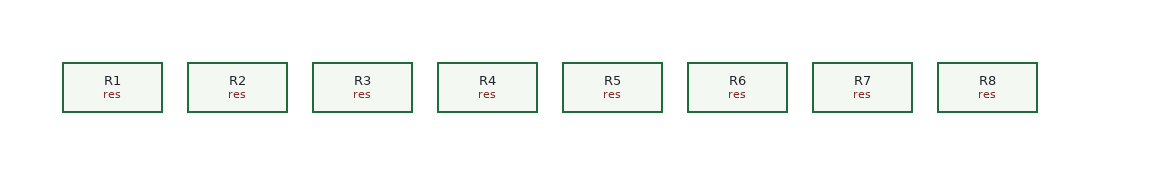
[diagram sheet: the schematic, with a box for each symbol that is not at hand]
v {xschem version=3.4.8RC file_version=1.3}
G {}
K {}
V {}
S {}
F {}
E {}
C {res.sym} 0 0 0 0 {name=R1 value=1 format="@name @pinlist expr(2-1)"}
C {res.sym} 100 0 0 0 {name=R2 value=1 format="@name @pinlist expr(2 - 1)"}
C {res.sym} 200 0 0 0 {name=R3 value=1 format="@name @pinlist expr(1e-3-1)"}
C {res.sym} 300 0 0 0 {name=R4 value=1 format="@name @pinlist expr_eng(1.5e-7)"}
C {res.sym} 400 0 0 0 {name=R5 value=1 format="@name @pinlist expr(W_N*2)"}
C {res.sym} 500 0 0 0 {name=R6 value=1 format="@name @pinlist expr('int((1 + 1)/2) * 1 / 1 * 0.29')"}
C {res.sym} 600 0 0 0 {name=R7 value=1 format="@name @pinlist expr_eng4(123456)"}
C {res.sym} 700 0 0 0 {name=R8 value=1 format="@name @pinlist expr(1/0)"}
